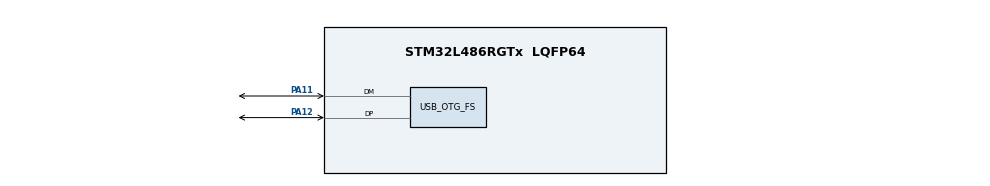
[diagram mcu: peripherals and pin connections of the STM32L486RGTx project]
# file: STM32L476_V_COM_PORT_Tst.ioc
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Mcu.Family=STM32L4
Mcu.Name=STM32L486RGTx
Mcu.Package=LQFP64
NVIC.PriorityGroup=NVIC_PRIORITYGROUP_4
PA11.Mode=Host_Only
PA11.Signal=USB_OTG_FS_DM
PA12.Mode=Host_Only
PA12.Signal=USB_OTG_FS_DP
RCC.HSE_VALUE=8000000
RCC.HSI_VALUE=16000000
RCC.LSE_VALUE=32768
RCC.MSI_VALUE=4000000
RCC.VCOOutputFreq_Value=32000000
USB_OTG_FS.VirtualMode=Host_Only
USB_OTG_FS.phy_itface=HCD_PHY_EMBEDDED
board=custom

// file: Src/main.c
/**
  ******************************************************************************
  * @file           : main.c
  * @brief          : Main program body
  ******************************************************************************
  * This notice applies to any and all portions of this file
  * that are not between comment pairs USER CODE BEGIN and
  * USER CODE END. Other portions of this file, whether
  * inserted by the user or by software development tools
  * are owned by their respective copyright owners.
  *
  * Copyright (c) 2019 STMicroelectronics International N.V.
  * All rights reserved.
  *
  * Redistribution and use in source and binary forms, with or without
  * modification, are permitted, provided that the following conditions are met:
  *
  * 1. Redistribution of source code must retain the above copyright notice,
  *    this list of conditions and the following disclaimer.
  * 2. Redistributions in binary form must reproduce the above copyright notice,
  *    this list of conditions and the following disclaimer in the documentation
  *    and/or other materials provided with the distribution.
  * 3. Neither the name of STMicroelectronics nor the names of other
  *    contributors to this software may be used to endorse or promote products
  *    derived from this software without specific written permission.
  * 4. This software, including modifications and/or derivative works of this
  *    software, must execute solely and exclusively on microcontroller or
  *    microprocessor devices manufactured by or for STMicroelectronics.
  * 5. Redistribution and use of this software other than as permitted under
  *    this license is void and will automatically terminate your rights under
  *    this license.
  *
  * THIS SOFTWARE IS PROVIDED BY STMICROELECTRONICS AND CONTRIBUTORS "AS IS"
  * AND ANY EXPRESS, IMPLIED OR STATUTORY WARRANTIES, INCLUDING, BUT NOT
  * LIMITED TO, THE IMPLIED WARRANTIES OF MERCHANTABILITY, FITNESS FOR A
  * PARTICULAR PURPOSE AND NON-INFRINGEMENT OF THIRD PARTY INTELLECTUAL PROPERTY
  * RIGHTS ARE DISCLAIMED TO THE FULLEST EXTENT PERMITTED BY LAW. IN NO EVENT
  * SHALL STMICROELECTRONICS OR CONTRIBUTORS BE LIABLE FOR ANY DIRECT, INDIRECT,
  * INCIDENTAL, SPECIAL, EXEMPLARY, OR CONSEQUENTIAL DAMAGES (INCLUDING, BUT NOT
  * LIMITED TO, PROCUREMENT OF SUBSTITUTE GOODS OR SERVICES; LOSS OF USE, DATA,
  * OR PROFITS; OR BUSINESS INTERRUPTION) HOWEVER CAUSED AND ON ANY THEORY OF
  * LIABILITY, WHETHER IN CONTRACT, STRICT LIABILITY, OR TORT (INCLUDING
  * NEGLIGENCE OR OTHERWISE) ARISING IN ANY WAY OUT OF THE USE OF THIS SOFTWARE,
  * EVEN IF ADVISED OF THE POSSIBILITY OF SUCH DAMAGE.
  *
  ******************************************************************************
  */
#include "main.h"
#include "stm32l4xx_hal.h"
#include "usb_device.h"

/* USER CODE BEGIN Includes */
#include "usbd_cdc_if.h"
#include <string.h>
/* USER CODE END Includes */

/* USER CODE BEGIN PV */
/* Private variables ---------------------------------------------------------*/

/* USER CODE END PV */

void SystemClock_Config(void);
static void MX_GPIO_Init(void);

/* USER CODE BEGIN PFP */
/* Private function prototypes -----------------------------------------------*/

/* USER CODE END PFP */

int main(void)
{
  /* USER CODE BEGIN 1 */
	uint8_t myBuf[20] = "Hello World \r\n";
  /* USER CODE END 1 */

  /* MCU Configuration----------------------------------------------------------*/

  /* Reset of all peripherals, Initializes the Flash interface and the Systick. */
  HAL_Init();

  /* Configure the system clock */
  SystemClock_Config();

  /* Initialize all configured peripherals */
  MX_GPIO_Init();
  MX_USB_DEVICE_Init();

  /* Infinite loop */
  while (1)
  {

  /* USER CODE BEGIN 3 */
	CDC_Transmit_FS(myBuf, strlen((char *)myBuf));
	HAL_Delay(500);
  }
  /* USER CODE END 3 */

}

void SystemClock_Config(void)
{

  RCC_OscInitTypeDef RCC_OscInitStruct;
  RCC_ClkInitTypeDef RCC_ClkInitStruct;
  RCC_PeriphCLKInitTypeDef PeriphClkInit;

    /**Initializes the CPU, AHB and APB busses clocks
    */
  RCC_OscInitStruct.OscillatorType = RCC_OSCILLATORTYPE_MSI;
  RCC_OscInitStruct.MSIState = RCC_MSI_ON;
  RCC_OscInitStruct.MSICalibrationValue = 0;
  RCC_OscInitStruct.MSIClockRange = RCC_MSIRANGE_6;
  RCC_OscInitStruct.PLL.PLLState = RCC_PLL_ON;
  RCC_OscInitStruct.PLL.PLLSource = RCC_PLLSOURCE_MSI;
  RCC_OscInitStruct.PLL.PLLM = 1;
  RCC_OscInitStruct.PLL.PLLN = 20;
  RCC_OscInitStruct.PLL.PLLP = RCC_PLLP_DIV7;
  RCC_OscInitStruct.PLL.PLLQ = RCC_PLLQ_DIV2;
  RCC_OscInitStruct.PLL.PLLR = RCC_PLLR_DIV2;
  if (HAL_RCC_OscConfig(&RCC_OscInitStruct) != HAL_OK)
  {
    _Error_Handler(__FILE__, __LINE__);
  }

    /**Initializes the CPU, AHB and APB busses clocks
    */
  RCC_ClkInitStruct.ClockType = RCC_CLOCKTYPE_HCLK|RCC_CLOCKTYPE_SYSCLK
                              |RCC_CLOCKTYPE_PCLK1|RCC_CLOCKTYPE_PCLK2;
  RCC_ClkInitStruct.SYSCLKSource = RCC_SYSCLKSOURCE_PLLCLK;
  RCC_ClkInitStruct.AHBCLKDivider = RCC_SYSCLK_DIV1;
  RCC_ClkInitStruct.APB1CLKDivider = RCC_HCLK_DIV1;
  RCC_ClkInitStruct.APB2CLKDivider = RCC_HCLK_DIV1;

  if (HAL_RCC_ClockConfig(&RCC_ClkInitStruct, FLASH_LATENCY_2) != HAL_OK)
  {
    _Error_Handler(__FILE__, __LINE__);
  }

  PeriphClkInit.PeriphClockSelection = RCC_PERIPHCLK_USB;
  PeriphClkInit.UsbClockSelection = RCC_USBCLKSOURCE_PLLSAI1;
  PeriphClkInit.PLLSAI1.PLLSAI1Source = RCC_PLLSOURCE_MSI;
  PeriphClkInit.PLLSAI1.PLLSAI1M = 1;
  PeriphClkInit.PLLSAI1.PLLSAI1N = 24;
  PeriphClkInit.PLLSAI1.PLLSAI1P = RCC_PLLP_DIV7;
  PeriphClkInit.PLLSAI1.PLLSAI1Q = RCC_PLLQ_DIV2;
  PeriphClkInit.PLLSAI1.PLLSAI1R = RCC_PLLR_DIV2;
  PeriphClkInit.PLLSAI1.PLLSAI1ClockOut = RCC_PLLSAI1_48M2CLK;
  if (HAL_RCCEx_PeriphCLKConfig(&PeriphClkInit) != HAL_OK)
  {
    _Error_Handler(__FILE__, __LINE__);
  }

    /**Configure the main internal regulator output voltage
    */
  if (HAL_PWREx_ControlVoltageScaling(PWR_REGULATOR_VOLTAGE_SCALE1) != HAL_OK)
  {
    _Error_Handler(__FILE__, __LINE__);
  }

    /**Configure the Systick interrupt time
    */
  HAL_SYSTICK_Config(HAL_RCC_GetHCLKFreq()/1000);

    /**Configure the Systick
    */
  HAL_SYSTICK_CLKSourceConfig(SYSTICK_CLKSOURCE_HCLK);

  /* SysTick_IRQn interrupt configuration */
  HAL_NVIC_SetPriority(SysTick_IRQn, 0, 0);
}

/** Configure pins as
        * Analog
        * Input
        * Output
        * EVENT_OUT
        * EXTI
*/
static void MX_GPIO_Init(void)
{

  /* GPIO Ports Clock Enable */
  __HAL_RCC_GPIOH_CLK_ENABLE();
  __HAL_RCC_GPIOA_CLK_ENABLE();

}

void _Error_Handler(char *file, int line)
{
  while(1)
  {
  }
}

/************************ (C) COPYRIGHT STMicroelectronics *****END OF FILE****/
